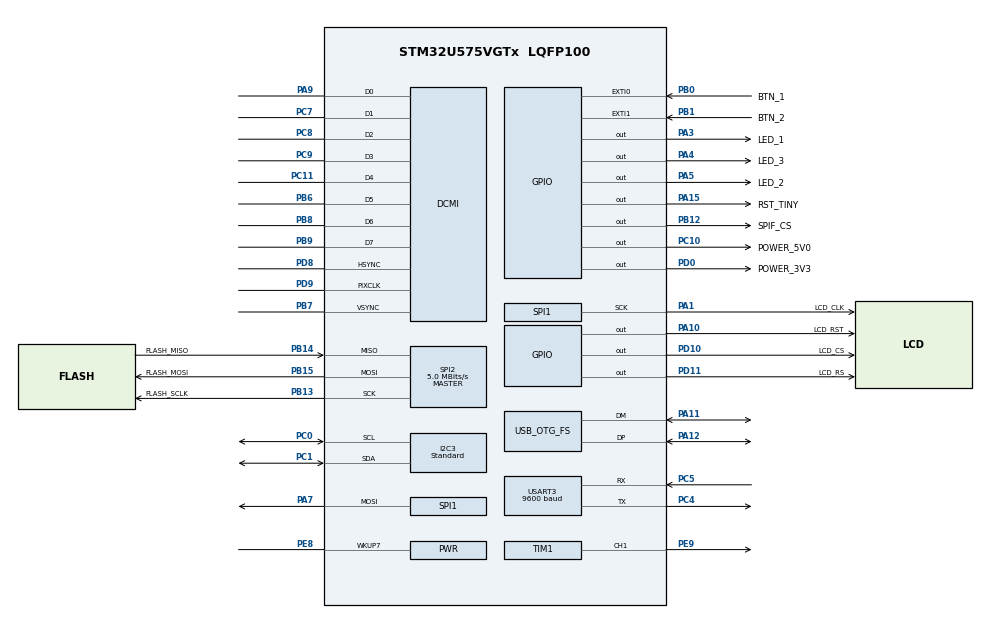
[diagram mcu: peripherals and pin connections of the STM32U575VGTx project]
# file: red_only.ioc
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CORTEX_M33_NS.MPU_Control=MPU_PRIVILEGED_DEFAULT
CORTEX_M33_NS.userName=CORTEX_M33
GPDMA1.CIRCULARMODE_GPDMACH0=ENABLE
GPDMA1.DESTDATAWIDTH_GPDMACH0=DMA_DEST_DATAWIDTH_WORD
GPDMA1.DESTINC_GPDMACH0=DMA_DINC_INCREMENTED
GPDMA1.IPHANDLE_GPDMACH0-SIMPLEREQUEST_GPDMACH0=__NULL
GPDMA1.REQUEST_GPDMACH0=GPDMA1_REQUEST_DCMI_PSSI
GPDMA1.SRCDATAWIDTH_GPDMACH0=DMA_SRC_DATAWIDTH_WORD
I2C3.I2C_Speed_Mode=I2C_Standard
I2C3.Timing=0x10909CEC
Mcu.Family=STM32U5
Mcu.Name=STM32U575VGTx
Mcu.Package=LQFP100
NVIC.DCMI_PSSI_IRQn=true\:0\:0\:false\:false\:true\:false\:true\:true\:true
NVIC.EXTI0_IRQn=true\:0\:0\:false\:false\:true\:false\:true\:true\:true
NVIC.EXTI1_IRQn=true\:0\:0\:false\:false\:true\:false\:true\:true\:true
NVIC.GPDMA1_Channel0_IRQn=true\:0\:0\:false\:false\:true\:false\:false\:true\:true
NVIC.OTG_FS_IRQn=true\:0\:0\:false\:false\:true\:false\:true\:true\:true
NVIC.PriorityGroup=NVIC_PRIORITYGROUP_4
NVIC.TIM6_IRQn=true\:15\:0\:false\:false\:true\:false\:false\:true\:true
NVIC.TimeBase=TIM6_IRQn
NVIC.TimeBaseIP=TIM6
PA1.GPIO_Label=LCD_CLK
PA1.Mode=TX_Only_Simplex_Unidirect_Master
PA1.Signal=SPI1_SCK
PA10.GPIO_Label=LCD_RST
PA10.GPIO_PuPd=GPIO_PULLUP
PA10.GPIO_Speed=GPIO_SPEED_FREQ_VERY_HIGH
PA10.PinState=GPIO_PIN_SET
PA10.Signal=GPIO_Output
PA11.GPIO_Speed=GPIO_SPEED_FREQ_VERY_HIGH
PA11.Mode=Device_Only
PA11.Signal=USB_OTG_FS_DM
PA12.GPIO_Speed=GPIO_SPEED_FREQ_VERY_HIGH
PA12.Mode=Device_Only
PA12.Signal=USB_OTG_FS_DP
PA13\ (JTMS/SWDIO).Mode=Serial_Wire
PA13\ (JTMS/SWDIO).Signal=DEBUG_JTMS-SWDIO
PA14\ (JTCK/SWCLK).Mode=Serial_Wire
PA14\ (JTCK/SWCLK).Signal=DEBUG_JTCK-SWCLK
PA15\ (JTDI).GPIO_Label=RST_TINY
PA15\ (JTDI).Signal=GPIO_Output
PA3.GPIO_Label=LED_1
PA3.Signal=GPIO_Output
PA4.GPIO_Label=LED_3
PA4.Signal=GPIO_Output
PA5.GPIO_Label=LED_2
PA5.Signal=GPIO_Output
PA6.Signal=SPI1_MISO
PA7.Mode=TX_Only_Simplex_Unidirect_Master
PA7.Signal=SPI1_MOSI
PA9.Mode=Slave_8_bits_External_Synchro
PA9.Signal=DCMI_D0
PB0.GPIO_Label=BTN_1
PB0.GPIO_ModeDefaultEXTI=GPIO_MODE_IT_FALLING
PB0.GPIO_PuPd=GPIO_PULLUP
PB0.Signal=GPXTI0
PB1.GPIO_Label=BTN_2
PB1.GPIO_ModeDefaultEXTI=GPIO_MODE_IT_FALLING
PB1.GPIO_PuPd=GPIO_PULLUP
PB1.Signal=GPXTI1
PB12.GPIO_Label=SPIF_CS
PB12.Signal=GPIO_Output
PB13.GPIO_Label=FLASH_SCLK
PB13.Mode=Full_Duplex_Master
PB13.Signal=SPI2_SCK
PB14.GPIO_Label=FLASH_MISO
PB14.Mode=Full_Duplex_Master
PB14.Signal=SPI2_MISO
PB15.GPIO_Label=FLASH_MOSI
PB15.Mode=Full_Duplex_Master
PB15.Signal=SPI2_MOSI
PB6.Mode=Slave_8_bits_External_Synchro
PB6.Signal=DCMI_D5
PB7.Mode=Slave_8_bits_External_Synchro
PB7.Signal=DCMI_VSYNC
PB8.Mode=Slave_8_bits_External_Synchro
PB8.Signal=DCMI_D6
PB9.Mode=Slave_8_bits_External_Synchro
PB9.Signal=DCMI_D7
PC0.GPIO_Pu=GPIO_PULLUP
PC0.GPIO_Speed=GPIO_SPEED_FREQ_VERY_HIGH
PC0.Mode=I2C
PC0.Signal=I2C3_SCL
PC1.GPIO_Pu=GPIO_PULLUP
PC1.GPIO_Speed=GPIO_SPEED_FREQ_VERY_HIGH
PC1.Mode=I2C
PC1.Signal=I2C3_SDA
PC10.GPIO_Label=POWER_5V0
PC10.GPIO_PuPd=GPIO_PULLDOWN
PC10.Signal=GPIO_Output
PC11.Mode=Slave_8_bits_External_Synchro
PC11.Signal=DCMI_D4
PC14-OSC32_IN\ (PC14).Mode=LSE-External-Oscillator
PC14-OSC32_IN\ (PC14).PinAttribute=Free
PC14-OSC32_IN\ (PC14).Signal=RCC_OSC32_IN
PC15-OSC32_OUT\ (PC15).Mode=LSE-External-Oscillator
PC15-OSC32_OUT\ (PC15).Signal=RCC_OSC32_OUT
PC4.Mode=Asynchronous
PC4.Signal=USART3_TX
PC5.Mode=Asynchronous
PC5.Signal=USART3_RX
PC7.Mode=Slave_8_bits_External_Synchro
PC7.Signal=DCMI_D1
PC8.Mode=Slave_8_bits_External_Synchro
PC8.Signal=DCMI_D2
PC9.Mode=Slave_8_bits_External_Synchro
PC9.Signal=DCMI_D3
PD0.GPIO_Label=POWER_3V3
PD0.GPIO_PuPd=GPIO_PULLDOWN
PD0.Signal=GPIO_Output
PD10.GPIO_Label=LCD_CS
PD10.GPIO_PuPd=GPIO_PULLDOWN
PD10.GPIO_Speed=GPIO_SPEED_FREQ_LOW
PD10.PinState=GPIO_PIN_SET
PD10.Signal=GPIO_Output
PD11.GPIO_Label=LCD_RS
PD11.GPIO_PuPd=GPIO_PULLUP
PD11.GPIO_Speed=GPIO_SPEED_FREQ_VERY_HIGH
PD11.PinState=GPIO_PIN_SET
PD11.Signal=GPIO_Output
PD8.Mode=Slave_8_bits_External_Synchro
PD8.Signal=DCMI_HSYNC
PD9.Mode=Slave_8_bits_External_Synchro
PD9.Signal=DCMI_PIXCLK
PE8.Mode=WakeUp7
PE8.Signal=PWR_WKUP7
PE9.Signal=S_TIM1_CH1
PH0-OSC_IN\ (PH0).Mode=HSE-External-Oscillator
PH0-OSC_IN\ (PH0).Signal=RCC_OSC_IN
PH1-OSC_OUT\ (PH1).Mode=HSE-External-Oscillator
PH1-OSC_OUT\ (PH1).Signal=RCC_OSC_OUT
ProjectManager.HeapSize=0x200
ProjectManager.StackSize=0x400
ProjectManager.TargetToolchain=Makefile
RCC.ADCFreq_Value=16000000
RCC.AHBFreq_Value=160000000
RCC.APB1Freq_Value=160000000
RCC.APB1TimFreq_Value=160000000
RCC.APB2Freq_Value=160000000
RCC.APB2TimFreq_Value=160000000
RCC.APB3CLKDivider=RCC_HCLK_DIV2
RCC.APB3Freq_Value=80000000
RCC.CortexFreq_Value=160000000
RCC.EPOD_VALUE=16000000
RCC.HCLKFreq_Value=160000000
RCC.HSE_VALUE=16000000
RCC.HSI48_VALUE=48000000
RCC.HSI_VALUE=16000000
RCC.LSIDIV_VALUE=32000
RCC.MSIClockRange=RCC_MSIRANGE_0
RCC.MSI_VALUE=48000000
RCC.PLL1R=1
RCC.PLL2FRACN=0
RCC.PLL3FRACN=0
RCC.PLLFRACN=0
RCC.PLLN=10
RCC.PLLSourceVirtual=RCC_PLLSOURCE_HSI
RCC.RTCClockSelection=RCC_RTCCLKSOURCE_LSE
RCC.SYSCLKFreq_VALUE=160000000
RCC.SYSCLKSource=RCC_SYSCLKSOURCE_PLLCLK
RCC.USBFreq_Value=48000000
RCC.VCOOutputFreq_Value=160000000
RCC.VDD_VALUE=3.3
SH.S_TIM1_CH1.0=TIM1_CH1,PWM Generation1 CH1
SPI1.BaudRatePrescaler=SPI_BAUDRATEPRESCALER_4
SPI1.CalculateBaudRate=40.0 MBits/s
SPI1.DataSize=SPI_DATASIZE_8BIT
SPI1.Direction=SPI_DIRECTION_2LINES_TXONLY
SPI1.Mode=SPI_MODE_MASTER
SPI1.VirtualType=VM_MASTER
SPI2.BaudRatePrescaler=SPI_BAUDRATEPRESCALER_32
SPI2.CalculateBaudRate=5.0 MBits/s
SPI2.DataSize=SPI_DATASIZE_8BIT
SPI2.Direction=SPI_DIRECTION_2LINES
SPI2.Mode=SPI_MODE_MASTER
SPI2.VirtualType=VM_MASTER
THREADX.TX_APP_MEM_POOL_SIZE=4096
TIM1.Channel-PWM\ Generation1\ CH1=TIM_CHANNEL_1
TIM1.PeriodNoDither=100-1
TIM1.Prescaler=2000-1
TIM1.PulseNoDither_1=80
USART3.BaudRate=9600
USART3.VirtualMode-Asynchronous=VM_ASYNC
USBX.BSP.number=1
USBX.Core_System=1
USBX.MAX_POWER_IN_MILLI_AMPER=0
USBX.USBD_HID_CUSTOM_EPIN_FS_BINTERVAL=5
USBX.USBD_HID_CUSTOM_EPIN_FS_MPS=64
USBX.USBD_HID_CUSTOM_EPIN_HS_BINTERVAL=5
USBX.USBD_HID_CUSTOM_EPIN_HS_MPS=64
USBX.USBD_HID_CUSTOM_EPOUT_ADDR=2
USBX.USBD_HID_CUSTOM_EPOUT_FS_BINTERVAL=5
USBX.USBD_HID_CUSTOM_EPOUT_FS_MPS=64
USBX.USBD_HID_CUSTOM_EPOUT_HS_MPS=64
USBX.USBD_PRODUCT_STRING=STM32U5 (USB Custom HID)
USBX.USBD_SERIAL_NUMBER=Custom_HID001
USBX.USBX_DEVICE_SYS_SIZE=8*1024
USBX.UX_DEVICE_APP_MEM_POOL_SIZE=16*1024
USBX.UX_DEVICE_CLASS_HID_INTERRUPT_OUT_SUPPORT=1
USBX.UX_DEVICE_CLASS_HID_MAX_EVENTS_QUEUE=16
USBX.UX_DEVICE_HID_CORE=1
USBX.UX_DEVICE_HID_CUSTOM=1
USBX.UX_Device_Controller=1
USBX.UX_Device_CoreStack=1
USBX.UX_ENFORCE_SAFE_ALIGNMENT=0
USBX.UX_SLAVE_REQUEST_DATA_MAX_LENGTH=64
USBX0.BSP.STBoard=false
USBX0.BSP.api=Unknown
USBX0.BSP.condition=SEMAOoUSBOoOTGOoFSOoDEVICEOoFOROoUSBX & \!DIE455
USBX0.BSP.instance=USB_OTG_FS
USBX0.BSP.ip=USB_OTG_FS
USBX0.BSP.mode=Device_Only
USBX0.BSP.name=USBDevice
USBX0.BSP.solution=USB_OTG_FS
USB_OTG_FS.VirtualMode=Device_Only
VP_GPDMA1_VS_GPDMACH0.Mode=SIMPLEREQUEST_GPDMACH0
VP_LPBAMQUEUE_VS_QUEUE.Mode=QUEUEMODE
VP_LPBAM_VS_SIG1.Mode=SmartRun
VP_LPBAM_VS_SIG4.Mode=LPDMA1
VP_MEMORYMAP_VS_MEMORYMAP.Mode=CurAppReg
VP_PWR_VS_LPOM.Mode=PowerOptimisation
VP_PWR_VS_SECSignals.Mode=Security/Privilege
VP_RCC_USB.Mode=CRS SYNC Source USB
VP_RTC_VS_RTC_Activate.Mode=RTC_Enabled
VP_RTC_VS_RTC_Calendar.Mode=RTC_Calendar
VP_SYS_VS_tim6.Mode=TIM6
VP_THREADX_VS_RTOSJjThreadXJjCoreJjDefault.Mode=Core_Default
VP_TIM1_VS_ClockSourceINT.Mode=Internal
VP_USBX_Core_System.Mode=Core_System
VP_USBX_UX\ Device\ Controller_FS.Mode=UX_Device_Controller_FS
VP_USBX_UX\ Device\ CoreStack_FS.Mode=UX_Device_CoreStack_FS
VP_USBX_UX\ Device\ HID_CORE_FS.Mode=UX_Device_class_HID_CORE_FS
VP_USBX_UX\ Device\ HID_CUSTOM_FS.Mode=UX_Device_class_HID_CUSTOM_FS
board=custom

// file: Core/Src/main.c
/* USER CODE BEGIN Header */
/**
 ******************************************************************************
 * @file           : main.c
 * @brief          : Main program body
 ******************************************************************************
 * @attention
 *
 * Copyright (c) 2025 STMicroelectronics.
 * All rights reserved.
 *
 * This software is licensed under terms that can be found in the LICENSE file
 * in the root directory of this software component.
 * If no LICENSE file comes with this software, it is provided AS-IS.
 *
 ******************************************************************************
 */
/* USER CODE END Header */
#include "main.h"
#include "dcmi.h"
#include "gpdma.h"
#include "i2c.h"
#include "rtc.h"
#include "spi.h"
#include "tim.h"
#include "usart.h"
#include "usb_otg.h"
#include "gpio.h"

/* USER CODE BEGIN Includes */
#include "tinycTask.h"
#include "spif.h"
#include "st7789.h"
/* USER CODE END Includes */

void SystemClock_Config(void);
static void MPU_Config(void);

int main(void)
{

  /* MCU Configuration--------------------------------------------------------*/

  /* MPU Configuration--------------------------------------------------------*/
  MPU_Config();

  /* Reset of all peripherals, Initializes the Flash interface and the Systick. */
  HAL_Init();

  /* Configure the system clock */
  SystemClock_Config();

  /* Initialize all configured peripherals */
  MX_GPIO_Init();
  MX_GPDMA1_Init();
  MX_DCMI_Init();
  MX_SPI1_Init();
  MX_TIM1_Init();
  MX_I2C3_Init();
  MX_SPI2_Init();
  MX_USART3_UART_Init();
  // MX_USB_OTG_FS_PCD_Init();
  MX_RTC_Init();
  /* USER CODE BEGIN 2 */

#if SLEEP_TEST
  printf("test_sleep begin\r\n");
  HAL_Delay(5000);
  // HAL_PWR_EnableWakeUpPin(PWR_WAKEUP_PIN1);
  HAL_PWR_EnableWakeUpPin(PWR_WAKEUP_PIN7_HIGH_3);
  HAL_RTCEx_DeactivateWakeUpTimer(&hrtc);
  __HAL_RTC_WAKEUPTIMER_CLEAR_FLAG(&hrtc, RTC_FLAG_WUTF);

  if (HAL_RTCEx_SetWakeUpTimer_IT(&hrtc, 60 * 60, RTC_WAKEUPCLOCK_CK_SPRE_16BITS, 0) != HAL_OK) // 1 hour wakeup
  {
    printf("fail to sleep\r\n");
  }

  printf("Enter shutdown\r\n");

  HAL_DCMI_Stop(&hdcmi);
  HAL_I2C_DeInit(&hi2c3);
  HAL_UART_DeInit(&huart3);
  HAL_TIM_Base_DeInit(&htim1);
  // HAL_PCD_DeInit(&hpcd_USB_OTG_FS);

  GPIO_All_Analog();

  __HAL_RCC_CRC_CLK_DISABLE();
  __HAL_RCC_SYSCFG_CLK_DISABLE();

  HAL_PWREx_EnableUltraLowPowerMode();

  HAL_PWREx_EnterSHUTDOWNMode();
#endif

#if TINYC_USE_LCD
  HAL_TIM_PWM_Start(&htim1, TIM_CHANNEL_1);

  __HAL_TIM_SET_COMPARE(&htim1, TIM_CHANNEL_1, 90); // set PWM duty cycle to 50%
  ST7789_Init();
// ST7789_Test();
#endif
   tinycTaskInit();

  // SPIF_HandleTypeDef hspif;
  // SPIF_Init(&hspif, &hspi2, SPIF_CS_GPIO_Port, SPIF_CS_Pin);
  // SPIF_Test(&hspif);

  /* USER CODE END 2 */

  /* Infinite loop */
  while (1)
  {

    /* USER CODE BEGIN 3 */
    // HAL_GPIO_TogglePin(LED_1_GPIO_Port, LED_1_Pin);
    // HAL_Delay(500);
    // HAL_GPIO_TogglePin(LED_1_GPIO_Port, LED_1_Pin);
    // HAL_Delay(500);
    TINYC_256_Task();
    HAL_Delay(10);
    // HAL_GPIO_TogglePin(LED_1_GPIO_Port, LED_1_Pin);
    // printf("Hello World!\r\n");
  }
  /* USER CODE END 3 */
}

void SystemClock_Config(void)
{
  RCC_OscInitTypeDef RCC_OscInitStruct = {0};
  RCC_ClkInitTypeDef RCC_ClkInitStruct = {0};

  /** Configure the main internal regulator output voltage
   */
  if (HAL_PWREx_ControlVoltageScaling(PWR_REGULATOR_VOLTAGE_SCALE1) != HAL_OK)
  {
    Error_Handler();
  }

  /** Configure LSE Drive Capability
   */
  HAL_PWR_EnableBkUpAccess();
  __HAL_RCC_LSEDRIVE_CONFIG(RCC_LSEDRIVE_LOW);

  /** Initializes the CPU, AHB and APB buses clocks
   */
  RCC_OscInitStruct.OscillatorType = RCC_OSCILLATORTYPE_HSI48 | RCC_OSCILLATORTYPE_LSE | RCC_OSCILLATORTYPE_MSI;
  RCC_OscInitStruct.LSEState = RCC_LSE_ON;
  RCC_OscInitStruct.HSI48State = RCC_HSI48_ON;
  RCC_OscInitStruct.MSIState = RCC_MSI_ON;
  RCC_OscInitStruct.MSICalibrationValue = RCC_MSICALIBRATION_DEFAULT;
  RCC_OscInitStruct.MSIClockRange = RCC_MSIRANGE_0;
  RCC_OscInitStruct.PLL.PLLState = RCC_PLL_ON;
  RCC_OscInitStruct.PLL.PLLSource = RCC_PLLSOURCE_MSI;
  RCC_OscInitStruct.PLL.PLLMBOOST = RCC_PLLMBOOST_DIV4;
  RCC_OscInitStruct.PLL.PLLM = 3;
  RCC_OscInitStruct.PLL.PLLN = 8;
  RCC_OscInitStruct.PLL.PLLP = 2;
  RCC_OscInitStruct.PLL.PLLQ = 2;
  RCC_OscInitStruct.PLL.PLLR = 1;
  RCC_OscInitStruct.PLL.PLLRGE = RCC_PLLVCIRANGE_1;
  RCC_OscInitStruct.PLL.PLLFRACN = 0;
  if (HAL_RCC_OscConfig(&RCC_OscInitStruct) != HAL_OK)
  {
    Error_Handler();
  }

  /** Initializes the CPU, AHB and APB buses clocks
   */
  RCC_ClkInitStruct.ClockType = RCC_CLOCKTYPE_HCLK | RCC_CLOCKTYPE_SYSCLK | RCC_CLOCKTYPE_PCLK1 | RCC_CLOCKTYPE_PCLK2 | RCC_CLOCKTYPE_PCLK3;
  RCC_ClkInitStruct.SYSCLKSource = RCC_SYSCLKSOURCE_PLLCLK;
  RCC_ClkInitStruct.AHBCLKDivider = RCC_SYSCLK_DIV1;
  RCC_ClkInitStruct.APB1CLKDivider = RCC_HCLK_DIV1;
  RCC_ClkInitStruct.APB2CLKDivider = RCC_HCLK_DIV1;
  RCC_ClkInitStruct.APB3CLKDivider = RCC_HCLK_DIV2;

  if (HAL_RCC_ClockConfig(&RCC_ClkInitStruct, FLASH_LATENCY_3) != HAL_OK)
  {
    Error_Handler();
  }
}

/* MPU Configuration */

static void MPU_Config(void)
{

  /* Disables the MPU */
  HAL_MPU_Disable();

  /* Enables the MPU */
  HAL_MPU_Enable(MPU_PRIVILEGED_DEFAULT);
}

void Error_Handler(void)
{
  __disable_irq();
  while (1)
  {
  }
}
